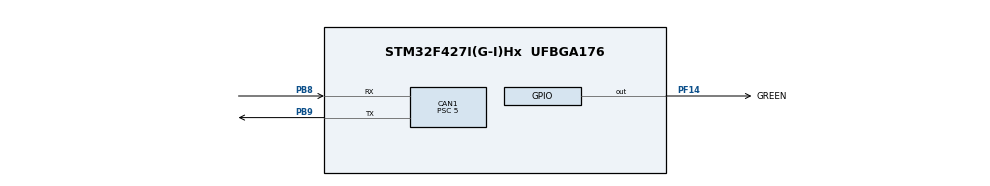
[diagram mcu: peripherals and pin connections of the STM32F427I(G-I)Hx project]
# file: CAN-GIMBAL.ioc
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CAN1.AWUM=ENABLE
CAN1.BS1=CAN_BS1_3TQ
CAN1.BS2=CAN_BS2_5TQ
CAN1.CalculateTimeQuantum=111.11111111111111
CAN1.Mode=CAN_MODE_NORMAL
CAN1.Prescaler=5
Mcu.Family=STM32F4
Mcu.Name=STM32F427I(G-I)Hx
Mcu.Package=UFBGA176
NVIC.CAN1_RX0_IRQn=true\:0\:0\:false\:false\:true\:true
NVIC.CAN1_TX_IRQn=true\:0\:0\:false\:false\:true\:true
NVIC.PriorityGroup=NVIC_PRIORITYGROUP_4
PB8.GPIO_PuPd=GPIO_NOPULL
PB8.Mode=Master
PB8.Signal=CAN1_RX
PB9.GPIO_PuPd=GPIO_NOPULL
PB9.Mode=Master
PB9.Signal=CAN1_TX
PF14.GPIO_Label=GREEN
PF14.GPIO_ModeDefaultOutputPP=GPIO_MODE_OUTPUT_PP
PF14.GPIO_PuPd=GPIO_NOPULL
PF14.GPIO_Speed=GPIO_SPEED_FREQ_LOW
PF14.PinState=GPIO_PIN_RESET
PF14.Signal=GPIO_Output
ProjectManager.HeapSize=0x200
ProjectManager.StackSize=0x400
ProjectManager.TargetToolchain=MDK-ARM V5
RCC.48MHZClocksFreq_Value=90000000
RCC.AHBFreq_Value=180000000
RCC.APB1CLKDivider=RCC_HCLK_DIV4
RCC.APB1Freq_Value=45000000
RCC.APB1TimFreq_Value=90000000
RCC.APB2CLKDivider=RCC_HCLK_DIV2
RCC.APB2Freq_Value=90000000
RCC.APB2TimFreq_Value=180000000
RCC.CortexFreq_Value=180000000
RCC.HCLKFreq_Value=180000000
RCC.HSE_VALUE=25000000
RCC.HSI_VALUE=16000000
RCC.LSE_VALUE=32768
RCC.PLLM=8
RCC.PLLN=180
RCC.SYSCLKFreq_VALUE=180000000
RCC.SYSCLKSource=RCC_SYSCLKSOURCE_PLLCLK
RCC.VCOOutputFreq_Value=360000000
board=custom

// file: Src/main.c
/**
  ******************************************************************************
  * @file           : main.c
  * @brief          : Main program body
  ******************************************************************************
  ** This notice applies to any and all portions of this file
  * that are not between comment pairs USER CODE BEGIN and
  * USER CODE END. Other portions of this file, whether
  * inserted by the user or by software development tools
  * are owned by their respective copyright owners.
  *
  * COPYRIGHT(c) 2018 STMicroelectronics
  *
  * Redistribution and use in source and binary forms, with or without modification,
  * are permitted provided that the following conditions are met:
  *   1. Redistributions of source code must retain the above copyright notice,
  *      this list of conditions and the following disclaimer.
  *   2. Redistributions in binary form must reproduce the above copyright notice,
  *      this list of conditions and the following disclaimer in the documentation
  *      and/or other materials provided with the distribution.
  *   3. Neither the name of STMicroelectronics nor the names of its contributors
  *      may be used to endorse or promote products derived from this software
  *      without specific prior written permission.
  *
  * THIS SOFTWARE IS PROVIDED BY THE COPYRIGHT HOLDERS AND CONTRIBUTORS "AS IS"
  * AND ANY EXPRESS OR IMPLIED WARRANTIES, INCLUDING, BUT NOT LIMITED TO, THE
  * IMPLIED WARRANTIES OF MERCHANTABILITY AND FITNESS FOR A PARTICULAR PURPOSE ARE
  * DISCLAIMED. IN NO EVENT SHALL THE COPYRIGHT HOLDER OR CONTRIBUTORS BE LIABLE
  * FOR ANY DIRECT, INDIRECT, INCIDENTAL, SPECIAL, EXEMPLARY, OR CONSEQUENTIAL
  * DAMAGES (INCLUDING, BUT NOT LIMITED TO, PROCUREMENT OF SUBSTITUTE GOODS OR
  * SERVICES; LOSS OF USE, DATA, OR PROFITS; OR BUSINESS INTERRUPTION) HOWEVER
  * CAUSED AND ON ANY THEORY OF LIABILITY, WHETHER IN CONTRACT, STRICT LIABILITY,
  * OR TORT (INCLUDING NEGLIGENCE OR OTHERWISE) ARISING IN ANY WAY OUT OF THE USE
  * OF THIS SOFTWARE, EVEN IF ADVISED OF THE POSSIBILITY OF SUCH DAMAGE.
  *
  ******************************************************************************
  */
#include "main.h"
#include "stm32f4xx_hal.h"

CAN_HandleTypeDef hcan1;

/* USER CODE BEGIN PV */
/* Private variables ---------------------------------------------------------*/

/* USER CODE END PV */

void SystemClock_Config(void);
static void MX_GPIO_Init(void);
static void MX_CAN1_Init(void);

/* USER CODE BEGIN PFP */
/* Private function prototypes -----------------------------------------------*/

/* USER CODE END PFP */

int main(void)
{

  /* MCU Configuration----------------------------------------------------------*/

  /* Reset of all peripherals, Initializes the Flash interface and the Systick. */
  HAL_Init();

  /* Configure the system clock */
  SystemClock_Config();

  /* Initialize all configured peripherals */
  MX_GPIO_Init();
  MX_CAN1_Init();
  /* USER CODE BEGIN 2 */
	//creating the CAN_TxHeaderTypeDef
	//the arguments for this can be found in stm32f4xx_hal_can.h line 191
	//not sure if these are correct
CAN_TxHeaderTypeDef pHeader;
pHeader.StdId = 0x000;
//pHeader.ExtId = 0;
pHeader.IDE = CAN_ID_STD;
pHeader.RTR = CAN_RTR_DATA;
pHeader.DLC = 8;
pHeader.TransmitGlobalTime = DISABLE;
//8bytes
uint8_t aData[8] ={0xFF, 0x00, 0xFF, 0x00, 0xFF, 0x00, 0x00, 0x00};

uint32_t mailbox0 = 0x00000001U;
	HAL_CAN_Start(&hcan1);

  /* USER CODE END 2 */

  /* Infinite loop */
  /* USER CODE BEGIN WHILE */
  while (1)
  {

		if (HAL_CAN_GetTxMailboxesFreeLevel(&hcan1) > 0){
			//stm32f4xx_hal_can.c defined there, line 872
			HAL_CAN_AddTxMessage(&hcan1,&pHeader, aData, &mailbox0);
		}

  /* USER CODE END WHILE */

  }

}

void SystemClock_Config(void)
{

 RCC_OscInitTypeDef RCC_OscInitStruct;
    RCC_ClkInitTypeDef RCC_ClkInitStruct;

    __HAL_RCC_PWR_CLK_ENABLE();

    __HAL_PWR_VOLTAGESCALING_CONFIG(PWR_REGULATOR_VOLTAGE_SCALE1);

    RCC_OscInitStruct.OscillatorType = RCC_OSCILLATORTYPE_HSE;
    RCC_OscInitStruct.HSEState       = RCC_HSE_ON;
    RCC_OscInitStruct.PLL.PLLState   = RCC_PLL_ON;
    RCC_OscInitStruct.PLL.PLLSource  = RCC_PLLSOURCE_HSE;
    RCC_OscInitStruct.PLL.PLLM       = 6;
    RCC_OscInitStruct.PLL.PLLN       = 180;
    RCC_OscInitStruct.PLL.PLLP       = RCC_PLLP_DIV2;
    RCC_OscInitStruct.PLL.PLLQ       = 4;
    if (HAL_RCC_OscConfig(&RCC_OscInitStruct) != HAL_OK)
    {
        Error_Handler();
    }

    if (HAL_PWREx_EnableOverDrive() != HAL_OK)
    {
        Error_Handler();
    }

    RCC_ClkInitStruct.ClockType      = RCC_CLOCKTYPE_HCLK | RCC_CLOCKTYPE_SYSCLK | RCC_CLOCKTYPE_PCLK1 | RCC_CLOCKTYPE_PCLK2;
    RCC_ClkInitStruct.SYSCLKSource   = RCC_SYSCLKSOURCE_PLLCLK;
    RCC_ClkInitStruct.AHBCLKDivider  = RCC_SYSCLK_DIV1;
    RCC_ClkInitStruct.APB1CLKDivider = RCC_HCLK_DIV4;
    RCC_ClkInitStruct.APB2CLKDivider = RCC_HCLK_DIV2;
    if (HAL_RCC_ClockConfig(&RCC_ClkInitStruct, FLASH_LATENCY_5) != HAL_OK)
    {
        Error_Handler();
    }

    HAL_SYSTICK_Config(HAL_RCC_GetHCLKFreq() / 1000);

    HAL_SYSTICK_CLKSourceConfig(SYSTICK_CLKSOURCE_HCLK);

    /* SysTick_IRQn interrupt configuration */
    HAL_NVIC_SetPriority(SysTick_IRQn, 15, 0);
}

/* CAN1 init function */
static void MX_CAN1_Init(void)
{

  hcan1.Instance = CAN1;
  hcan1.Init.Prescaler = 5;
  hcan1.Init.Mode = CAN_MODE_NORMAL;
  hcan1.Init.SyncJumpWidth = CAN_SJW_1TQ;
  hcan1.Init.TimeSeg1 = CAN_BS1_3TQ;
  hcan1.Init.TimeSeg2 = CAN_BS2_5TQ;
  hcan1.Init.TimeTriggeredMode = DISABLE;
  hcan1.Init.AutoBusOff = DISABLE;
  hcan1.Init.AutoWakeUp = ENABLE;
  hcan1.Init.AutoRetransmission = DISABLE;
  hcan1.Init.ReceiveFifoLocked = DISABLE;
  hcan1.Init.TransmitFifoPriority = DISABLE;
  if (HAL_CAN_Init(&hcan1) != HAL_OK)
  {
    _Error_Handler(__FILE__, __LINE__);
  }

}

/** Configure pins as
        * Analog
        * Input
        * Output
        * EVENT_OUT
        * EXTI
*/
static void MX_GPIO_Init(void)
{

  GPIO_InitTypeDef GPIO_InitStruct;

  /* GPIO Ports Clock Enable */
  __HAL_RCC_GPIOB_CLK_ENABLE();
  __HAL_RCC_GPIOF_CLK_ENABLE();

  /*Configure GPIO pin Output Level */
  HAL_GPIO_WritePin(GREEN_GPIO_Port, GREEN_Pin, GPIO_PIN_RESET);

  /*Configure GPIO pin : GREEN_Pin */
  GPIO_InitStruct.Pin = GREEN_Pin;
  GPIO_InitStruct.Mode = GPIO_MODE_OUTPUT_PP;
  GPIO_InitStruct.Pull = GPIO_NOPULL;
  GPIO_InitStruct.Speed = GPIO_SPEED_FREQ_LOW;
  HAL_GPIO_Init(GREEN_GPIO_Port, &GPIO_InitStruct);

}

void _Error_Handler(char *file, int line)
{
  /* USER CODE BEGIN Error_Handler_Debug */
  /* User can add his own implementation to report the HAL error return state */
  while(1)
  {
		HAL_Delay(1000);
			HAL_GPIO_TogglePin(GREEN_GPIO_Port, GREEN_Pin);
  }
  /* USER CODE END Error_Handler_Debug */
}

/************************ (C) COPYRIGHT STMicroelectronics *****END OF FILE****/
